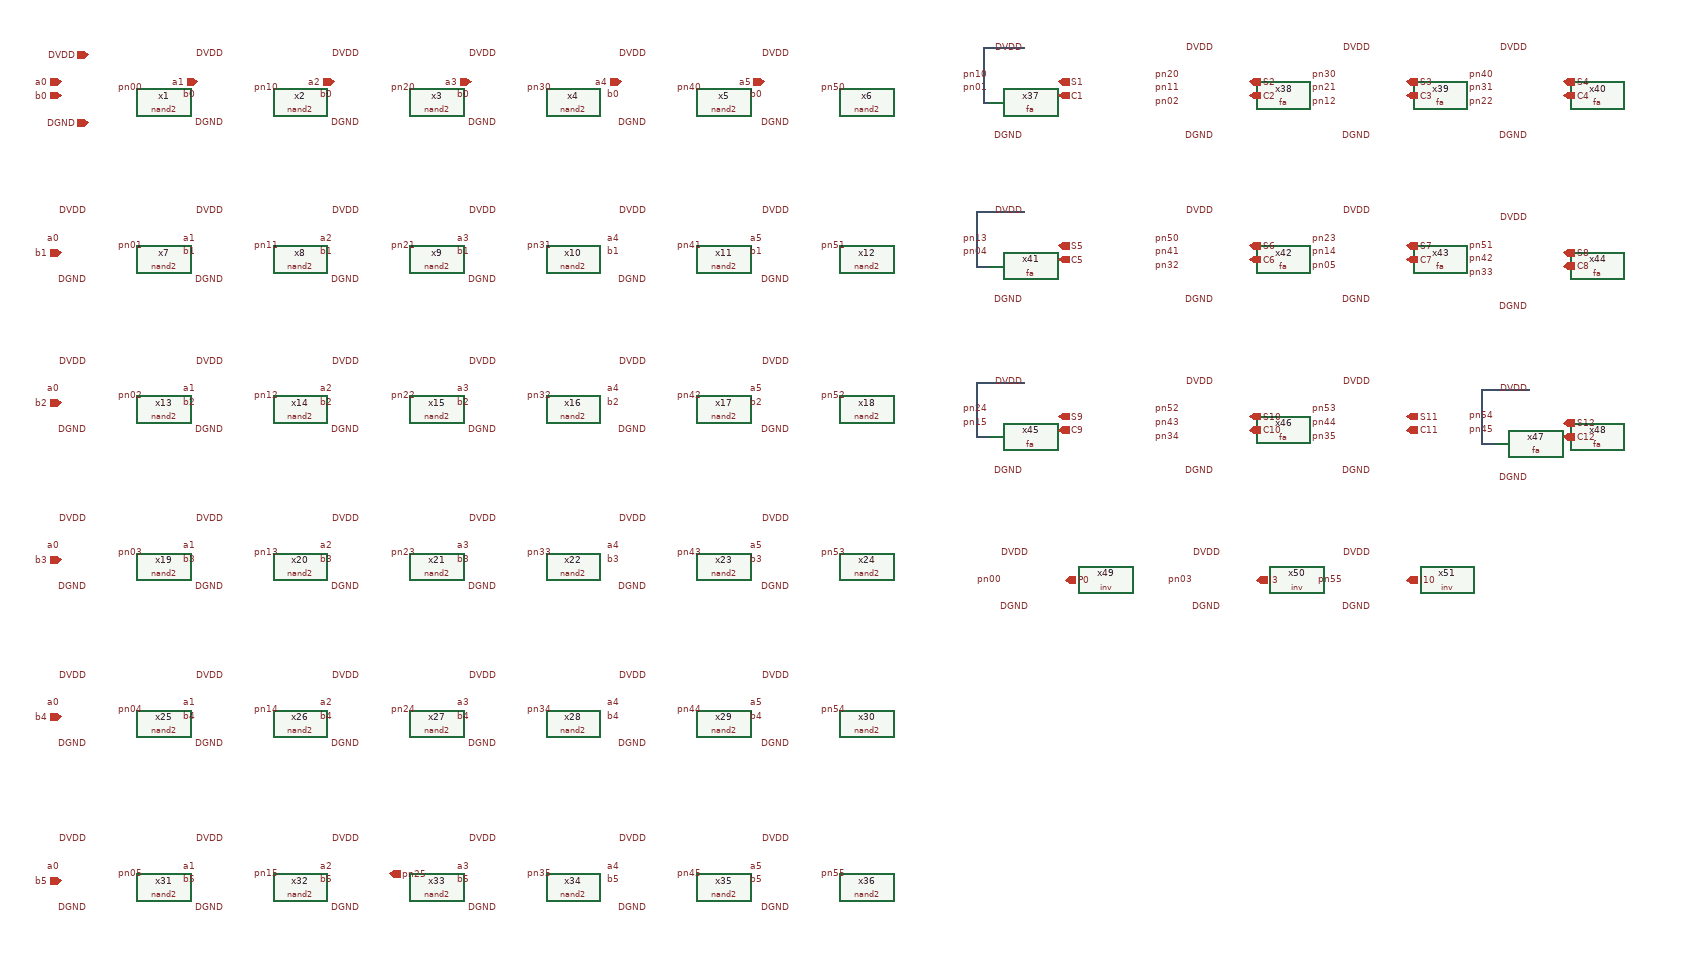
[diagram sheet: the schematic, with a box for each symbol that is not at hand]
v {xschem version=3.4.8RC file_version=1.3}
G {}
K {}
V {}
S {}
F {}
E {}
N 1170 -20 1180 -20 {lab=DVDD}
N 1170 -100 1170 -20 {lab=DVDD}
N 1170 -100 1230 -100 {lab=DVDD}
N 1160 220 1180 220 {lab=DVDD}
N 1160 140 1160 220 {lab=DVDD}
N 1160 140 1230 140 {lab=DVDD}
N 1160 470 1180 470 {lab=DVDD}
N 1160 390 1160 470 {lab=DVDD}
N 1160 390 1230 390 {lab=DVDD}
N 1900 480 1920 480 {lab=DVDD}
N 1900 400 1900 480 {lab=DVDD}
N 1900 400 1970 400 {lab=DVDD}
C {nand2.sym} -30 -20 0 0 {name=x1}
C {lab_pin.sym} -100 -40 2 0 {name=p3 sig_type=std_logic lab=pn00}
C {iopin.sym} -140 -90 3 0 {name=p4 lab=DVDD}
C {iopin.sym} -140 10 1 0 {name=p5 lab=DGND}
C {nand2.sym} 170 -20 0 0 {name=x2}
C {lab_pin.sym} 20 -30 0 0 {name=p7 sig_type=std_logic lab=b0}
C {lab_pin.sym} 100 -40 2 0 {name=p8 sig_type=std_logic lab=pn10}
C {lab_pin.sym} 60 -90 1 0 {name=p9 sig_type=std_logic lab=DVDD}
C {lab_pin.sym} 60 10 3 0 {name=p10 sig_type=std_logic lab=DGND}
C {ipin.sym} -180 -50 0 0 {name=p11 lab=a0}
C {ipin.sym} -180 -30 0 0 {name=p1 lab=b0}
C {ipin.sym} 20 -50 0 0 {name=p2 lab=a1}
C {nand2.sym} 370 -20 0 0 {name=x3}
C {lab_pin.sym} 220 -30 0 0 {name=p6 sig_type=std_logic lab=b0}
C {lab_pin.sym} 300 -40 2 0 {name=p12 sig_type=std_logic lab=pn20}
C {lab_pin.sym} 260 -90 1 0 {name=p13 sig_type=std_logic lab=DVDD}
C {lab_pin.sym} 260 10 3 0 {name=p14 sig_type=std_logic lab=DGND}
C {ipin.sym} 220 -50 0 0 {name=p15 lab=a2}
C {nand2.sym} 570 -20 0 0 {name=x4}
C {lab_pin.sym} 420 -30 0 0 {name=p16 sig_type=std_logic lab=b0}
C {lab_pin.sym} 500 -40 2 0 {name=p17 sig_type=std_logic lab=pn30}
C {lab_pin.sym} 460 -90 1 0 {name=p18 sig_type=std_logic lab=DVDD}
C {lab_pin.sym} 460 10 3 0 {name=p19 sig_type=std_logic lab=DGND}
C {ipin.sym} 420 -50 0 0 {name=p20 lab=a3}
C {nand2.sym} 790 -20 0 0 {name=x5}
C {lab_pin.sym} 640 -30 0 0 {name=p21 sig_type=std_logic lab=b0}
C {lab_pin.sym} 720 -40 2 0 {name=p22 sig_type=std_logic lab=pn40}
C {lab_pin.sym} 680 -90 1 0 {name=p23 sig_type=std_logic lab=DVDD}
C {lab_pin.sym} 680 10 3 0 {name=p24 sig_type=std_logic lab=DGND}
C {ipin.sym} 640 -50 0 0 {name=p25 lab=a4}
C {nand2.sym} 1000 -20 0 0 {name=x6}
C {lab_pin.sym} 850 -30 0 0 {name=p26 sig_type=std_logic lab=b0}
C {lab_pin.sym} 930 -40 2 0 {name=p27 sig_type=std_logic lab=pn50}
C {lab_pin.sym} 890 -90 1 0 {name=p28 sig_type=std_logic lab=DVDD}
C {lab_pin.sym} 890 10 3 0 {name=p29 sig_type=std_logic lab=DGND}
C {ipin.sym} 850 -50 0 0 {name=p30 lab=a5}
C {nand2.sym} -30 210 0 0 {name=x7}
C {lab_pin.sym} -100 190 2 0 {name=p31 sig_type=std_logic lab=pn01}
C {nand2.sym} 170 210 0 0 {name=x8}
C {lab_pin.sym} 100 190 2 0 {name=p35 sig_type=std_logic lab=pn11}
C {lab_pin.sym} 60 140 1 0 {name=p36 sig_type=std_logic lab=DVDD}
C {lab_pin.sym} 60 240 3 0 {name=p37 sig_type=std_logic lab=DGND}
C {ipin.sym} -180 200 0 0 {name=p39 lab=b1}
C {nand2.sym} 370 210 0 0 {name=x9}
C {lab_pin.sym} 300 190 2 0 {name=p42 sig_type=std_logic lab=pn21}
C {lab_pin.sym} 260 140 1 0 {name=p43 sig_type=std_logic lab=DVDD}
C {lab_pin.sym} 260 240 3 0 {name=p44 sig_type=std_logic lab=DGND}
C {nand2.sym} 570 210 0 0 {name=x10}
C {lab_pin.sym} 500 190 2 0 {name=p47 sig_type=std_logic lab=pn31}
C {lab_pin.sym} 460 140 1 0 {name=p48 sig_type=std_logic lab=DVDD}
C {lab_pin.sym} 460 240 3 0 {name=p49 sig_type=std_logic lab=DGND}
C {nand2.sym} 790 210 0 0 {name=x11}
C {lab_pin.sym} 720 190 2 0 {name=p52 sig_type=std_logic lab=pn41}
C {lab_pin.sym} 680 140 1 0 {name=p53 sig_type=std_logic lab=DVDD}
C {lab_pin.sym} 680 240 3 0 {name=p54 sig_type=std_logic lab=DGND}
C {nand2.sym} 1000 210 0 0 {name=x12}
C {lab_pin.sym} 930 190 2 0 {name=p57 sig_type=std_logic lab=pn51}
C {lab_pin.sym} 890 140 1 0 {name=p58 sig_type=std_logic lab=DVDD}
C {lab_pin.sym} 890 240 3 0 {name=p59 sig_type=std_logic lab=DGND}
C {lab_pin.sym} -140 140 1 0 {name=p32 sig_type=std_logic lab=DVDD}
C {lab_pin.sym} -140 240 3 0 {name=p33 sig_type=std_logic lab=DGND}
C {lab_pin.sym} -180 180 0 0 {name=p38 sig_type=std_logic lab=a0}
C {lab_pin.sym} 20 180 0 0 {name=p40 sig_type=std_logic lab=a1}
C {lab_pin.sym} 220 180 0 0 {name=p45 sig_type=std_logic lab=a2}
C {lab_pin.sym} 420 180 0 0 {name=p50 sig_type=std_logic lab=a3}
C {lab_pin.sym} 640 180 0 0 {name=p55 sig_type=std_logic lab=a4}
C {lab_pin.sym} 850 180 0 0 {name=p60 sig_type=std_logic lab=a5}
C {lab_pin.sym} 20 200 0 0 {name=p34 sig_type=std_logic lab=b1}
C {lab_pin.sym} 220 200 0 0 {name=p41 sig_type=std_logic lab=b1}
C {lab_pin.sym} 420 200 0 0 {name=p46 sig_type=std_logic lab=b1}
C {lab_pin.sym} 640 200 0 0 {name=p51 sig_type=std_logic lab=b1}
C {lab_pin.sym} 850 200 0 0 {name=p56 sig_type=std_logic lab=b1}
C {nand2.sym} -30 430 0 0 {name=x13}
C {lab_pin.sym} -100 410 2 0 {name=p61 sig_type=std_logic lab=pn02}
C {nand2.sym} 170 430 0 0 {name=x14}
C {lab_pin.sym} 100 410 2 0 {name=p62 sig_type=std_logic lab=pn12}
C {lab_pin.sym} 60 360 1 0 {name=p63 sig_type=std_logic lab=DVDD}
C {lab_pin.sym} 60 460 3 0 {name=p64 sig_type=std_logic lab=DGND}
C {ipin.sym} -180 420 0 0 {name=p65 lab=b2}
C {nand2.sym} 370 430 0 0 {name=x15}
C {lab_pin.sym} 300 410 2 0 {name=p66 sig_type=std_logic lab=pn22}
C {lab_pin.sym} 260 360 1 0 {name=p67 sig_type=std_logic lab=DVDD}
C {lab_pin.sym} 260 460 3 0 {name=p68 sig_type=std_logic lab=DGND}
C {nand2.sym} 570 430 0 0 {name=x16}
C {lab_pin.sym} 500 410 2 0 {name=p69 sig_type=std_logic lab=pn32}
C {lab_pin.sym} 460 360 1 0 {name=p70 sig_type=std_logic lab=DVDD}
C {lab_pin.sym} 460 460 3 0 {name=p71 sig_type=std_logic lab=DGND}
C {nand2.sym} 790 430 0 0 {name=x17}
C {lab_pin.sym} 720 410 2 0 {name=p72 sig_type=std_logic lab=pn42}
C {lab_pin.sym} 680 360 1 0 {name=p73 sig_type=std_logic lab=DVDD}
C {lab_pin.sym} 680 460 3 0 {name=p74 sig_type=std_logic lab=DGND}
C {nand2.sym} 1000 430 0 0 {name=x18}
C {lab_pin.sym} 930 410 2 0 {name=p75 sig_type=std_logic lab=pn52}
C {lab_pin.sym} 890 360 1 0 {name=p76 sig_type=std_logic lab=DVDD}
C {lab_pin.sym} 890 460 3 0 {name=p77 sig_type=std_logic lab=DGND}
C {lab_pin.sym} -140 360 1 0 {name=p78 sig_type=std_logic lab=DVDD}
C {lab_pin.sym} -140 460 3 0 {name=p79 sig_type=std_logic lab=DGND}
C {lab_pin.sym} -180 400 0 0 {name=p80 sig_type=std_logic lab=a0}
C {lab_pin.sym} 20 400 0 0 {name=p81 sig_type=std_logic lab=a1}
C {lab_pin.sym} 220 400 0 0 {name=p82 sig_type=std_logic lab=a2}
C {lab_pin.sym} 420 400 0 0 {name=p83 sig_type=std_logic lab=a3}
C {lab_pin.sym} 640 400 0 0 {name=p84 sig_type=std_logic lab=a4}
C {lab_pin.sym} 850 400 0 0 {name=p85 sig_type=std_logic lab=a5}
C {lab_pin.sym} 20 420 0 0 {name=p86 sig_type=std_logic lab=b2}
C {lab_pin.sym} 220 420 0 0 {name=p87 sig_type=std_logic lab=b2}
C {lab_pin.sym} 420 420 0 0 {name=p88 sig_type=std_logic lab=b2}
C {lab_pin.sym} 640 420 0 0 {name=p89 sig_type=std_logic lab=b2}
C {lab_pin.sym} 850 420 0 0 {name=p90 sig_type=std_logic lab=b2}
C {nand2.sym} -30 660 0 0 {name=x19}
C {lab_pin.sym} -100 640 2 0 {name=p91 sig_type=std_logic lab=pn03}
C {nand2.sym} 170 660 0 0 {name=x20}
C {lab_pin.sym} 100 640 2 0 {name=p92 sig_type=std_logic lab=pn13}
C {lab_pin.sym} 60 590 1 0 {name=p93 sig_type=std_logic lab=DVDD}
C {lab_pin.sym} 60 690 3 0 {name=p94 sig_type=std_logic lab=DGND}
C {ipin.sym} -180 650 0 0 {name=p95 lab=b3}
C {nand2.sym} 370 660 0 0 {name=x21}
C {lab_pin.sym} 300 640 2 0 {name=p96 sig_type=std_logic lab=pn23}
C {lab_pin.sym} 260 590 1 0 {name=p97 sig_type=std_logic lab=DVDD}
C {lab_pin.sym} 260 690 3 0 {name=p98 sig_type=std_logic lab=DGND}
C {nand2.sym} 570 660 0 0 {name=x22}
C {lab_pin.sym} 500 640 2 0 {name=p99 sig_type=std_logic lab=pn33}
C {lab_pin.sym} 460 590 1 0 {name=p100 sig_type=std_logic lab=DVDD}
C {lab_pin.sym} 460 690 3 0 {name=p101 sig_type=std_logic lab=DGND}
C {nand2.sym} 790 660 0 0 {name=x23}
C {lab_pin.sym} 720 640 2 0 {name=p102 sig_type=std_logic lab=pn43}
C {lab_pin.sym} 680 590 1 0 {name=p103 sig_type=std_logic lab=DVDD}
C {lab_pin.sym} 680 690 3 0 {name=p104 sig_type=std_logic lab=DGND}
C {nand2.sym} 1000 660 0 0 {name=x24}
C {lab_pin.sym} 930 640 2 0 {name=p105 sig_type=std_logic lab=pn53}
C {lab_pin.sym} 890 590 1 0 {name=p106 sig_type=std_logic lab=DVDD}
C {lab_pin.sym} 890 690 3 0 {name=p107 sig_type=std_logic lab=DGND}
C {lab_pin.sym} -140 590 1 0 {name=p108 sig_type=std_logic lab=DVDD}
C {lab_pin.sym} -140 690 3 0 {name=p109 sig_type=std_logic lab=DGND}
C {lab_pin.sym} -180 630 0 0 {name=p110 sig_type=std_logic lab=a0}
C {lab_pin.sym} 20 630 0 0 {name=p111 sig_type=std_logic lab=a1}
C {lab_pin.sym} 220 630 0 0 {name=p112 sig_type=std_logic lab=a2}
C {lab_pin.sym} 420 630 0 0 {name=p113 sig_type=std_logic lab=a3}
C {lab_pin.sym} 640 630 0 0 {name=p114 sig_type=std_logic lab=a4}
C {lab_pin.sym} 850 630 0 0 {name=p115 sig_type=std_logic lab=a5}
C {lab_pin.sym} 20 650 0 0 {name=p116 sig_type=std_logic lab=b3}
C {lab_pin.sym} 220 650 0 0 {name=p117 sig_type=std_logic lab=b3}
C {lab_pin.sym} 420 650 0 0 {name=p118 sig_type=std_logic lab=b3}
C {lab_pin.sym} 640 650 0 0 {name=p119 sig_type=std_logic lab=b3}
C {lab_pin.sym} 850 650 0 0 {name=p120 sig_type=std_logic lab=b3}
C {nand2.sym} -30 890 0 0 {name=x25}
C {lab_pin.sym} -100 870 2 0 {name=p121 sig_type=std_logic lab=pn04}
C {nand2.sym} 170 890 0 0 {name=x26}
C {lab_pin.sym} 100 870 2 0 {name=p122 sig_type=std_logic lab=pn14}
C {lab_pin.sym} 60 820 1 0 {name=p123 sig_type=std_logic lab=DVDD}
C {lab_pin.sym} 60 920 3 0 {name=p124 sig_type=std_logic lab=DGND}
C {ipin.sym} -180 880 0 0 {name=p125 lab=b4}
C {nand2.sym} 370 890 0 0 {name=x27}
C {lab_pin.sym} 300 870 2 0 {name=p126 sig_type=std_logic lab=pn24}
C {lab_pin.sym} 260 820 1 0 {name=p127 sig_type=std_logic lab=DVDD}
C {lab_pin.sym} 260 920 3 0 {name=p128 sig_type=std_logic lab=DGND}
C {nand2.sym} 570 890 0 0 {name=x28}
C {lab_pin.sym} 500 870 2 0 {name=p129 sig_type=std_logic lab=pn34}
C {lab_pin.sym} 460 820 1 0 {name=p130 sig_type=std_logic lab=DVDD}
C {lab_pin.sym} 460 920 3 0 {name=p131 sig_type=std_logic lab=DGND}
C {nand2.sym} 790 890 0 0 {name=x29}
C {lab_pin.sym} 720 870 2 0 {name=p132 sig_type=std_logic lab=pn44}
C {lab_pin.sym} 680 820 1 0 {name=p133 sig_type=std_logic lab=DVDD}
C {lab_pin.sym} 680 920 3 0 {name=p134 sig_type=std_logic lab=DGND}
C {nand2.sym} 1000 890 0 0 {name=x30}
C {lab_pin.sym} 930 870 2 0 {name=p135 sig_type=std_logic lab=pn54}
C {lab_pin.sym} 890 820 1 0 {name=p136 sig_type=std_logic lab=DVDD}
C {lab_pin.sym} 890 920 3 0 {name=p137 sig_type=std_logic lab=DGND}
C {lab_pin.sym} -140 820 1 0 {name=p138 sig_type=std_logic lab=DVDD}
C {lab_pin.sym} -140 920 3 0 {name=p139 sig_type=std_logic lab=DGND}
C {lab_pin.sym} -180 860 0 0 {name=p140 sig_type=std_logic lab=a0}
C {lab_pin.sym} 20 860 0 0 {name=p141 sig_type=std_logic lab=a1}
C {lab_pin.sym} 220 860 0 0 {name=p142 sig_type=std_logic lab=a2}
C {lab_pin.sym} 420 860 0 0 {name=p143 sig_type=std_logic lab=a3}
C {lab_pin.sym} 640 860 0 0 {name=p144 sig_type=std_logic lab=a4}
C {lab_pin.sym} 850 860 0 0 {name=p145 sig_type=std_logic lab=a5}
C {lab_pin.sym} 20 880 0 0 {name=p146 sig_type=std_logic lab=b4}
C {lab_pin.sym} 220 880 0 0 {name=p147 sig_type=std_logic lab=b4}
C {lab_pin.sym} 420 880 0 0 {name=p148 sig_type=std_logic lab=b4}
C {lab_pin.sym} 640 880 0 0 {name=p149 sig_type=std_logic lab=b4}
C {lab_pin.sym} 850 880 0 0 {name=p150 sig_type=std_logic lab=b4}
C {nand2.sym} -30 1130 0 0 {name=x31}
C {lab_pin.sym} -100 1110 2 0 {name=p151 sig_type=std_logic lab=pn05}
C {nand2.sym} 170 1130 0 0 {name=x32}
C {lab_pin.sym} 100 1110 2 0 {name=p152 sig_type=std_logic lab=pn15}
C {lab_pin.sym} 60 1060 1 0 {name=p153 sig_type=std_logic lab=DVDD}
C {lab_pin.sym} 60 1160 3 0 {name=p154 sig_type=std_logic lab=DGND}
C {ipin.sym} -180 1120 0 0 {name=p155 lab=b5}
C {nand2.sym} 370 1130 0 0 {name=x33}
C {lab_pin.sym} 260 1060 1 0 {name=p157 sig_type=std_logic lab=DVDD}
C {lab_pin.sym} 260 1160 3 0 {name=p158 sig_type=std_logic lab=DGND}
C {nand2.sym} 570 1130 0 0 {name=x34}
C {lab_pin.sym} 500 1110 2 0 {name=p159 sig_type=std_logic lab=pn35}
C {lab_pin.sym} 460 1060 1 0 {name=p160 sig_type=std_logic lab=DVDD}
C {lab_pin.sym} 460 1160 3 0 {name=p161 sig_type=std_logic lab=DGND}
C {nand2.sym} 790 1130 0 0 {name=x35}
C {lab_pin.sym} 720 1110 2 0 {name=p162 sig_type=std_logic lab=pn45}
C {lab_pin.sym} 680 1060 1 0 {name=p163 sig_type=std_logic lab=DVDD}
C {lab_pin.sym} 680 1160 3 0 {name=p164 sig_type=std_logic lab=DGND}
C {nand2.sym} 1000 1130 0 0 {name=x36}
C {lab_pin.sym} 930 1110 2 0 {name=p165 sig_type=std_logic lab=pn55}
C {lab_pin.sym} 890 1060 1 0 {name=p166 sig_type=std_logic lab=DVDD}
C {lab_pin.sym} 890 1160 3 0 {name=p167 sig_type=std_logic lab=DGND}
C {lab_pin.sym} -140 1060 1 0 {name=p168 sig_type=std_logic lab=DVDD}
C {lab_pin.sym} -140 1160 3 0 {name=p169 sig_type=std_logic lab=DGND}
C {lab_pin.sym} -180 1100 0 0 {name=p170 sig_type=std_logic lab=a0}
C {lab_pin.sym} 20 1100 0 0 {name=p171 sig_type=std_logic lab=a1}
C {lab_pin.sym} 220 1100 0 0 {name=p172 sig_type=std_logic lab=a2}
C {lab_pin.sym} 420 1100 0 0 {name=p173 sig_type=std_logic lab=a3}
C {lab_pin.sym} 640 1100 0 0 {name=p174 sig_type=std_logic lab=a4}
C {lab_pin.sym} 850 1100 0 0 {name=p175 sig_type=std_logic lab=a5}
C {lab_pin.sym} 20 1120 0 0 {name=p176 sig_type=std_logic lab=b5}
C {lab_pin.sym} 220 1120 0 0 {name=p177 sig_type=std_logic lab=b5}
C {lab_pin.sym} 420 1120 0 0 {name=p178 sig_type=std_logic lab=b5}
C {lab_pin.sym} 640 1120 0 0 {name=p179 sig_type=std_logic lab=b5}
C {lab_pin.sym} 850 1120 0 0 {name=p180 sig_type=std_logic lab=b5}
C {fa.sym} 1330 -30 0 0 {name=x37}
C {lab_pin.sym} 1180 -60 0 0 {name=p181 sig_type=std_logic lab=pn10}
C {lab_pin.sym} 1180 -40 0 0 {name=p182 sig_type=std_logic lab=pn01}
C {lab_pin.sym} 1230 -100 1 0 {name=p183 sig_type=std_logic lab=DVDD}
C {lab_pin.sym} 1230 30 3 0 {name=p184 sig_type=std_logic lab=DGND}
C {opin.sym} 1280 -50 0 0 {name=p185 lab=S1}
C {opin.sym} 1280 -30 0 0 {name=p186 lab=C1}
C {fa.sym} 1610 -30 0 0 {name=x38}
C {lab_pin.sym} 1510 -100 1 0 {name=p187 sig_type=std_logic lab=DVDD}
C {lab_pin.sym} 1510 30 3 0 {name=p188 sig_type=std_logic lab=DGND}
C {lab_pin.sym} 1460 -60 0 0 {name=p189 sig_type=std_logic lab=pn20}
C {lab_pin.sym} 1460 -40 0 0 {name=p190 sig_type=std_logic lab=pn11}
C {lab_pin.sym} 1460 -20 0 0 {name=p191 sig_type=std_logic lab=pn02}
C {opin.sym} 1560 -50 0 0 {name=p192 lab=S2}
C {opin.sym} 1560 -30 0 0 {name=p193 lab=C2}
C {fa.sym} 1840 -30 0 0 {name=x39}
C {lab_pin.sym} 1740 -100 1 0 {name=p194 sig_type=std_logic lab=DVDD}
C {lab_pin.sym} 1740 30 3 0 {name=p195 sig_type=std_logic lab=DGND}
C {lab_pin.sym} 1690 -60 0 0 {name=p196 sig_type=std_logic lab=pn30}
C {lab_pin.sym} 1690 -40 0 0 {name=p197 sig_type=std_logic lab=pn21}
C {lab_pin.sym} 1690 -20 0 0 {name=p198 sig_type=std_logic lab=pn12}
C {opin.sym} 1790 -50 0 0 {name=p199 lab=S3}
C {opin.sym} 1790 -30 0 0 {name=p200 lab=C3}
C {fa.sym} 2070 -30 0 0 {name=x40}
C {lab_pin.sym} 1970 -100 1 0 {name=p201 sig_type=std_logic lab=DVDD}
C {lab_pin.sym} 1970 30 3 0 {name=p202 sig_type=std_logic lab=DGND}
C {lab_pin.sym} 1920 -60 0 0 {name=p203 sig_type=std_logic lab=pn40}
C {lab_pin.sym} 1920 -40 0 0 {name=p204 sig_type=std_logic lab=pn31}
C {lab_pin.sym} 1920 -20 0 0 {name=p205 sig_type=std_logic lab=pn22}
C {opin.sym} 2020 -50 0 0 {name=p206 lab=S4}
C {opin.sym} 2020 -30 0 0 {name=p207 lab=C4}
C {fa.sym} 1330 210 0 0 {name=x41}
C {lab_pin.sym} 1230 140 1 0 {name=p208 sig_type=std_logic lab=DVDD}
C {lab_pin.sym} 1230 270 3 0 {name=p209 sig_type=std_logic lab=DGND}
C {lab_pin.sym} 1180 180 0 0 {name=p210 sig_type=std_logic lab=pn13}
C {lab_pin.sym} 1180 200 0 0 {name=p211 sig_type=std_logic lab=pn04}
C {opin.sym} 1280 190 0 0 {name=p213 lab=S5}
C {opin.sym} 1280 210 0 0 {name=p214 lab=C5}
C {fa.sym} 1610 210 0 0 {name=x42}
C {lab_pin.sym} 1510 140 1 0 {name=p212 sig_type=std_logic lab=DVDD}
C {lab_pin.sym} 1510 270 3 0 {name=p215 sig_type=std_logic lab=DGND}
C {lab_pin.sym} 1460 180 0 0 {name=p216 sig_type=std_logic lab=pn50}
C {lab_pin.sym} 1460 200 0 0 {name=p217 sig_type=std_logic lab=pn41}
C {lab_pin.sym} 1460 220 0 0 {name=p218 sig_type=std_logic lab=pn32}
C {opin.sym} 1560 190 0 0 {name=p219 lab=S6}
C {opin.sym} 1560 210 0 0 {name=p220 lab=C6}
C {fa.sym} 1840 210 0 0 {name=x43}
C {lab_pin.sym} 1740 140 1 0 {name=p221 sig_type=std_logic lab=DVDD}
C {lab_pin.sym} 1740 270 3 0 {name=p222 sig_type=std_logic lab=DGND}
C {lab_pin.sym} 1690 180 0 0 {name=p223 sig_type=std_logic lab=pn23}
C {lab_pin.sym} 1690 200 0 0 {name=p224 sig_type=std_logic lab=pn14}
C {lab_pin.sym} 1690 220 0 0 {name=p225 sig_type=std_logic lab=pn05}
C {opin.sym} 1790 190 0 0 {name=p226 lab=S7}
C {opin.sym} 1790 210 0 0 {name=p227 lab=C7}
C {fa.sym} 2070 220 0 0 {name=x44}
C {lab_pin.sym} 1970 150 1 0 {name=p228 sig_type=std_logic lab=DVDD}
C {lab_pin.sym} 1970 280 3 0 {name=p229 sig_type=std_logic lab=DGND}
C {lab_pin.sym} 1920 190 0 0 {name=p230 sig_type=std_logic lab=pn51}
C {lab_pin.sym} 1920 210 0 0 {name=p231 sig_type=std_logic lab=pn42}
C {lab_pin.sym} 1920 230 0 0 {name=p232 sig_type=std_logic lab=pn33}
C {opin.sym} 2020 200 0 0 {name=p233 lab=S8}
C {opin.sym} 2020 220 0 0 {name=p234 lab=C8}
C {fa.sym} 1330 460 0 0 {name=x45}
C {lab_pin.sym} 1230 390 1 0 {name=p235 sig_type=std_logic lab=DVDD}
C {lab_pin.sym} 1230 520 3 0 {name=p236 sig_type=std_logic lab=DGND}
C {lab_pin.sym} 1180 430 0 0 {name=p237 sig_type=std_logic lab=pn24}
C {lab_pin.sym} 1180 450 0 0 {name=p238 sig_type=std_logic lab=pn15}
C {opin.sym} 1280 440 0 0 {name=p239 lab=S9}
C {opin.sym} 1280 460 0 0 {name=p240 lab=C9}
C {fa.sym} 1610 460 0 0 {name=x46}
C {lab_pin.sym} 1510 390 1 0 {name=p241 sig_type=std_logic lab=DVDD}
C {lab_pin.sym} 1510 520 3 0 {name=p242 sig_type=std_logic lab=DGND}
C {lab_pin.sym} 1460 430 0 0 {name=p243 sig_type=std_logic lab=pn52}
C {lab_pin.sym} 1460 450 0 0 {name=p244 sig_type=std_logic lab=pn43}
C {lab_pin.sym} 1460 470 0 0 {name=p245 sig_type=std_logic lab=pn34}
C {opin.sym} 1560 440 0 0 {name=p246 lab=S10}
C {opin.sym} 1560 460 0 0 {name=p247 lab=C10}
C {fa.sym} 1840 460 0 0 {name=x47}
C {lab_pin.sym} 1740 390 1 0 {name=p248 sig_type=std_logic lab=DVDD}
C {lab_pin.sym} 1740 520 3 0 {name=p249 sig_type=std_logic lab=DGND}
C {lab_pin.sym} 1690 430 0 0 {name=p250 sig_type=std_logic lab=pn53}
C {lab_pin.sym} 1690 450 0 0 {name=p251 sig_type=std_logic lab=pn44}
C {lab_pin.sym} 1690 470 0 0 {name=p252 sig_type=std_logic lab=pn35}
C {opin.sym} 1790 440 0 0 {name=p253 lab=S11}
C {opin.sym} 1790 460 0 0 {name=p254 lab=C11}
C {fa.sym} 2070 470 0 0 {name=x48}
C {lab_pin.sym} 1970 400 1 0 {name=p255 sig_type=std_logic lab=DVDD}
C {lab_pin.sym} 1970 530 3 0 {name=p256 sig_type=std_logic lab=DGND}
C {lab_pin.sym} 1920 440 0 0 {name=p257 sig_type=std_logic lab=pn54}
C {lab_pin.sym} 1920 460 0 0 {name=p258 sig_type=std_logic lab=pn45}
C {opin.sym} 2020 450 0 0 {name=p260 lab=S12}
C {opin.sym} 2020 470 0 0 {name=p261 lab=C12}
C {opin.sym} 300 1110 0 0 {name=p156 lab=pn25}
C {inv.sym} 1350 680 0 0 {name=x49}
C {lab_pin.sym} 1200 680 0 0 {name=p259 sig_type=std_logic lab=pn00}
C {opin.sym} 1290 680 0 0 {name=p262 lab=P0}
C {lab_pin.sym} 1240 640 1 0 {name=p263 sig_type=std_logic lab=DVDD}
C {lab_pin.sym} 1240 720 3 0 {name=p264 sig_type=std_logic lab=DGND}
C {inv.sym} 1630 680 0 0 {name=x50}
C {lab_pin.sym} 1480 680 0 0 {name=p265 sig_type=std_logic lab=pn03}
C {opin.sym} 1570 680 0 0 {name=p266 lab=I3}
C {lab_pin.sym} 1520 640 1 0 {name=p267 sig_type=std_logic lab=DVDD}
C {lab_pin.sym} 1520 720 3 0 {name=p268 sig_type=std_logic lab=DGND}
C {inv.sym} 1850 680 0 0 {name=x51}
C {lab_pin.sym} 1700 680 0 0 {name=p269 sig_type=std_logic lab=pn55}
C {opin.sym} 1790 680 0 0 {name=p270 lab=I10}
C {lab_pin.sym} 1740 640 1 0 {name=p271 sig_type=std_logic lab=DVDD}
C {lab_pin.sym} 1740 720 3 0 {name=p272 sig_type=std_logic lab=DGND}
